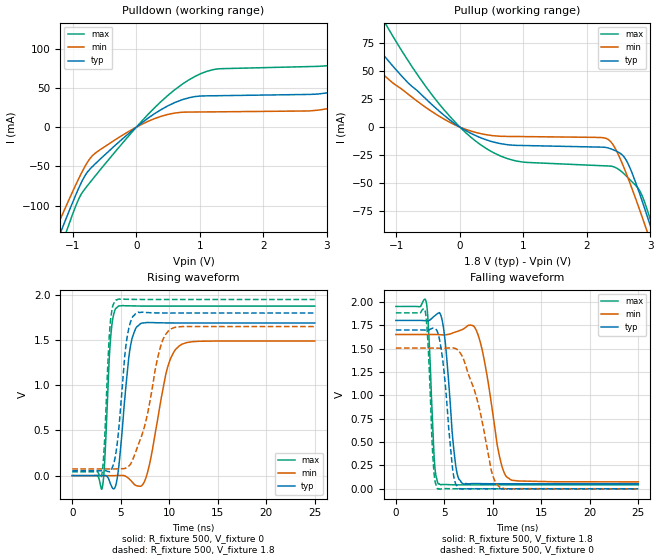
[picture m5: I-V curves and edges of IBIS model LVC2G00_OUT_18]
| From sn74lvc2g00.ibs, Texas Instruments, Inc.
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[Model]   LVC2G00_OUT_18
Model_type  Output
Vref =   0
Rref =   1000
Cref =   30p
Vmeas =   0.9
| variable   typ   min   max
C_comp   9.75pF   6.49pF   16.55pF
| C_pullup   8.84pF   6.49pF   9.71pF
| C_pulldown   10.67pF   6.61pF   16.55pF
[Temperature Range]   40   100   -40
| Ambient temperature   25   85   -40
[Voltage range]   1.8   1.65   1.95
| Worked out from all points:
|   slope of the pulldown table from 0 to 0.27 V, typ, clamps not added: 16.6 ohm
|   slope of the pullup table from 0 to 0.27 V, typ, clamps not added: 33.1 ohm
|   rising waveform, R_fixture 500, V_fixture 0: 20-80 % time 871ps typ, 1.53ns min, 493ps max; typ from 0 V to 1.69 V
|   falling waveform, R_fixture 500, V_fixture 1.8: 20-80 % time 794ps typ, 1.41ns min, 469ps max; typ from 1.8 V to 0.054 V
|   rising waveform, R_fixture 500, V_fixture 1.8: 20-80 % time 862ps typ, 1.9ns min, 483ps max; typ from 0.054 V to 1.8 V
|   falling waveform, R_fixture 500, V_fixture 0: 20-80 % time 877ps typ, 2.1ns min, 462ps max; typ from 1.7 V to 0 V
[Pulldown]
| LVC2G00_OUT_18
|   Voltage   I(typ)   I(min)   I(max)
-5.5V     -1.024A    -932.8mA   -1.143A
-1.25V    -145.7mA   -126.9mA   -167.2mA
-1.105V   -116mA     -100.2mA   -133.6mA
-650mV    -46.91mA   -33.3mA    -62.35mA
825mV     37.35mA    19.19mA    60.06mA
3.115V    45.51mA    25.21mA    79.67mA
3.75V     64.63mA    36.25mA    102.7mA
4.19V     79.74mA    21.53mA    128.8mA
4.47V     45.53mA    21.68mA    147.1mA
4.725V    44.49mA    21.83mA    132.4mA
5.015V    44.72mA    22mA       83.01mA
11V       50.72mA    25.33mA    92.94mA
[Pullup]
| LVC2G00_OUT_18
|   Voltage   I(typ)   I(min)   I(max)
-5.5V     463.8mA    356.2mA    652.9mA
-2.025V   127.2mA    95.17mA    184.5mA
-1.53V    88.09mA    64.89mA    129.3mA
-1.185V   63.28mA    45.93mA    93.85mA
-315mV    13.77mA    9.383mA    19.91mA
390mV     -10.87mA   -6.54mA    -18.23mA
990mV     -16.43mA   -8.453mA   -31.26mA
2.34V     -18.76mA   -11.2mA    -34.79mA
2.62V     -29.72mA   -41.58mA   -43.75mA
2.95V     -79.83mA   -93.7mA    -74.05mA
3.09V     -104.6mA   -117.3mA   -99.67mA
11V       -1.709A    -1.61A     -1.847A
[Ramp]
| LVC2G00_OUT_18
| variable   typ   min   max
dV/dt_r   1.10/9.55E-10   0.96/1.69E-09   1.22/5.50E-10
dV/dt_f   1.10/9.00E-10   1.00/1.57E-09   1.19/4.96E-10
R_load = 500
[Rising Waveform]
| LVC2G00_OUT_18
R_fixture =   500
C_fixture =   0
L_fixture =   0
V_fixture =   0
V_fixture_min = 0
V_fixture_max = 0
|   Time   V(typ)   V(min)   V(max)
0s        111.1pV    7.498nV    3.005nV
3.08ns    890.2uV    -71.22uV   -139.2mV
3.975ns   -99.86mV   -93.88uV   1.554V
4.73ns    43.52mV    1.986mV    1.874V
5.905ns   1.37V      -40.82mV   1.88V
6.985ns   1.678V     -117.8mV   1.877V
7.935ns   1.694V     113.8mV    1.877V
9.805ns   1.691V     1.191V     1.877V
11.02ns   1.69V      1.436V     1.877V
24.99ns   1.69V      1.49V      1.877V
[Falling Waveform]
| LVC2G00_OUT_18
R_fixture =   500
C_fixture =   0
L_fixture =   0
V_fixture =   1.8
V_fixture_min = 1.65
V_fixture_max = 1.95
|   Time   V(typ)   V(min)   V(max)
0s        1.8V       1.65V      1.95V
3.135ns   1.796V     1.65V      1.997V
3.955ns   1.845V     1.65V      326.6mV
4.395ns   1.879V     1.649V     51.32mV
5.045ns   1.613V     1.647V     45.43mV
6.195ns   232.7mV    1.678V     42.03mV
6.855ns   56.72mV    1.702V     41.68mV
8.595ns   55.18mV    1.609V     41.85mV
11.47ns   53.66mV    122.3mV    41.88mV
24.99ns   53.6mV     73.95mV    41.88mV
[Rising Waveform]
| LVC2G00_OUT_18
R_fixture =   500
C_fixture =   0
L_fixture =   0
V_fixture =   1.8
V_fixture_min = 1.65
V_fixture_max = 1.95
|   Time   V(typ)   V(min)   V(max)
0s        53.59mV    73.89mV    41.88mV
3.015ns   54.08mV    73.84mV    -5.701mV
3.29ns    56.58mV    73.8mV     309.5mV
3.875ns   43.25mV    73.86mV    1.637V
4.47ns    232.3mV    74.32mV    1.943V
5.615ns   1.507V     89.69mV    1.952V
6.61ns    1.801V     283.3mV    1.951V
9.095ns   1.801V     1.427V     1.95V
10.1ns    1.8V       1.619V     1.95V
24.99ns   1.8V       1.65V      1.95V
[Falling Waveform]
| LVC2G00_OUT_18
R_fixture =   500
C_fixture =   0
L_fixture =   0
V_fixture =   0
V_fixture_min = 0
V_fixture_max = 0
|   Time   V(typ)   V(min)   V(max)
0s        1.699V     1.505V     1.882V
3.015ns   1.697V     1.505V     1.906V
3.325ns   1.696V     1.505V     1.534V
3.89ns    1.718V     1.505V     233mV
4.32ns    1.67V      1.504V     -1.828mV
4.93ns    1.29V      1.503V     333.5uV
5.865ns   198.4mV    1.508V     259.6uV
6.495ns   2.21mV     1.472V     -200.6uV
10.7ns    29.26uV    16.62mV    2.635uV
24.99ns   8.489uV    22.77uV    3.874uV
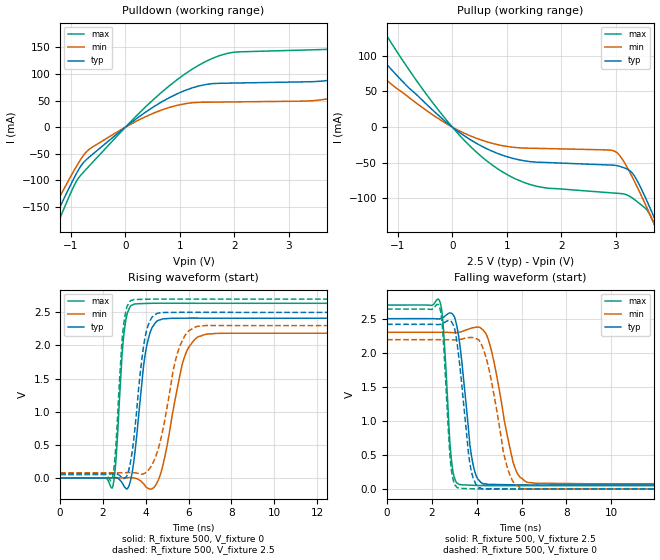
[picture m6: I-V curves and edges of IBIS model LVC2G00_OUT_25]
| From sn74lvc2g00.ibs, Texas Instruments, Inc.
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[Model]   LVC2G00_OUT_25
Model_type  Output
Vref =   0
Rref =   500
Cref =   30p
Vmeas =   1.25
| variable   typ   min   max
C_comp   9.50pF   6.28pF   13.67pF
| C_pullup   9.22pF   6.28pF   10.84pF
| C_pulldown   9.79pF   6.28pF   13.67pF
[Temperature Range]   40   100   -40
| Ambient temperature   25   85   -40
[Voltage range]   2.5   2.3   2.7
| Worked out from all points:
|   slope of the pulldown table from 0 to 0.375 V, typ, clamps not added: 13.1 ohm
|   slope of the pullup table from 0 to 0.375 V, typ, clamps not added: 19 ohm
|   rising waveform, R_fixture 500, V_fixture 0: 20-80 % time 479ps typ, 770ps min, 299ps max; typ from 0 V to 2.41 V
|   falling waveform, R_fixture 500, V_fixture 2.5: 20-80 % time 451ps typ, 760ps min, 277ps max; typ from 2.5 V to 0.06 V
|   rising waveform, R_fixture 500, V_fixture 2.5: 20-80 % time 483ps typ, 803ps min, 297ps max; typ from 0.06 V to 2.5 V
|   falling waveform, R_fixture 500, V_fixture 0: 20-80 % time 445ps typ, 715ps min, 275ps max; typ from 2.42 V to 0 V
[Pulldown]
| LVC2G00_OUT_25
|   Voltage   I(typ)   I(min)   I(max)
-5.5V     -1.065A    -962.2mA   -1.199A
-1.53V    -221.1mA   -193.8mA   -251.2mA
-1.17V    -142.7mA   -123.7mA   -162.8mA
-670mV    -56.67mA   -41.91mA   -73.36mA
520mV     38.43mA    26.46mA    52.49mA
1.485V    80.34mA    46.87mA    124mA
3.845V    90.19mA    55.77mA    148mA
5.34V     158.2mA    106.6mA    232.1mA
5.845V    188.2mA    52.6mA     277.9mA
6.525V    93.64mA    53.14mA    300.5mA
7.565V    94.13mA    54.13mA    160.8mA
11V       99.66mA    57.57mA    168.9mA
[Pullup]
| LVC2G00_OUT_25
|   Voltage   I(typ)   I(min)   I(max)
-5.5V     540.5mA    425.9mA    755.1mA
-2.25V    184.3mA    140.8mA    263.9mA
-1.8V     141.1mA    106.9mA    203.3mA
-1.375V   102.6mA    76.95mA    148.9mA
-70mV     4.265mA    3.049mA    6.405mA
730mV     -33.72mA   -22.66mA   -53.01mA
1.56V     -49.18mA   -29.79mA   -83.17mA
2.995V    -53.63mA   -34.3mA    -92.61mA
3.315V    -65.3mA    -71.46mA   -99.87mA
3.565V    -101.9mA   -111.4mA   -115.4mA
3.75V     -134.3mA   -142.6mA   -143.5mA
11V       -1.614A    -1.516A    -1.761A
[Ramp]
| LVC2G00_OUT_25
| variable   typ   min   max
dV/dt_r   1.55/5.35E-10   1.41/8.47E-10   1.68/3.29E-10
dV/dt_f   1.51/4.93E-10   1.38/8.23E-10   1.64/2.96E-10
R_load = 500
[Rising Waveform]
| LVC2G00_OUT_25
R_fixture =   500
C_fixture =   0
L_fixture =   0
V_fixture =   0
V_fixture_min = 0
V_fixture_max = 0
|   Time   V(typ)   V(min)   V(max)
0s        123.6pV    5.747nV    2.756nV
2.44ns    1.412mV    -38.45uV   -147.8mV
2.605ns   3.732mV    -160.8uV   268.9mV
2.99ns    -128.3mV   630.5uV    2.207V
3.465ns   308.9mV    -1.698mV   2.626V
4.01ns    1.936V     -137.1mV   2.635V
4.6ns     2.383V     -21.45mV   2.638V
5.765ns   2.413V     1.783V     2.638V
6.715ns   2.413V     2.162V     2.637V
24.99ns   2.412V     2.184V     2.637V
[Falling Waveform]
| LVC2G00_OUT_25
R_fixture =   500
C_fixture =   0
L_fixture =   0
V_fixture =   2.5
V_fixture_min = 2.3
V_fixture_max = 2.7
|   Time   V(typ)   V(min)   V(max)
0s        2.5V       2.3V       2.7V
2.35ns    2.498V     2.3V       2.756V
2.505ns   2.518V     2.3V       2.393V
2.87ns    2.581V     2.296V     427.8mV
3.23ns    2.155V     2.302V     66.3mV
3.77ns    477.1mV    2.362V     55.47mV
4.28ns    77.28mV    2.333V     50.42mV
5.625ns   61.73mV    387.1mV    48.89mV
6.26ns    60.08mV    97.17mV    49.17mV
24.99ns   60.1mV     77.09mV    49.34mV
[Rising Waveform]
| LVC2G00_OUT_25
R_fixture =   500
C_fixture =   0
L_fixture =   0
V_fixture =   2.5
V_fixture_min = 2.3
V_fixture_max = 2.7
|   Time   V(typ)   V(min)   V(max)
0s        60.06mV    77.04mV    49.31mV
2.425ns   61.28mV    77.01mV    -20.94mV
2.585ns   64.25mV    76.9mV     407mV
2.945ns   -3.35mV    77.42mV    2.256V
3.32ns    303.2mV    81.63mV    2.682V
3.95ns    2.092V     71.01mV    2.698V
4.56ns    2.488V     416.3mV    2.701V
5.5ns     2.5V       1.905V     2.701V
6.375ns   2.501V     2.286V     2.7V
24.99ns   2.5V       2.3V       2.7V
[Falling Waveform]
| LVC2G00_OUT_25
R_fixture =   500
C_fixture =   0
L_fixture =   0
V_fixture =   0
V_fixture_min = 0
V_fixture_max = 0
|   Time   V(typ)   V(min)   V(max)
0s        2.416V     2.191V     2.64V
2.33ns    2.414V     2.192V     2.679V
2.48ns    2.428V     2.192V     2.323V
2.84ns    2.463V     2.188V     367.4mV
3.155ns   2.057V     2.19V      16.47mV
3.71ns    345.3mV    2.224V     4.819mV
4.255ns   2.025mV    2.085V     898.4uV
5.33ns    2.084mV    353.4mV    -431.4uV
6.025ns   40.29uV    6.866mV    -164.5uV
24.99ns   29.16uV    44.31uV    23.85uV
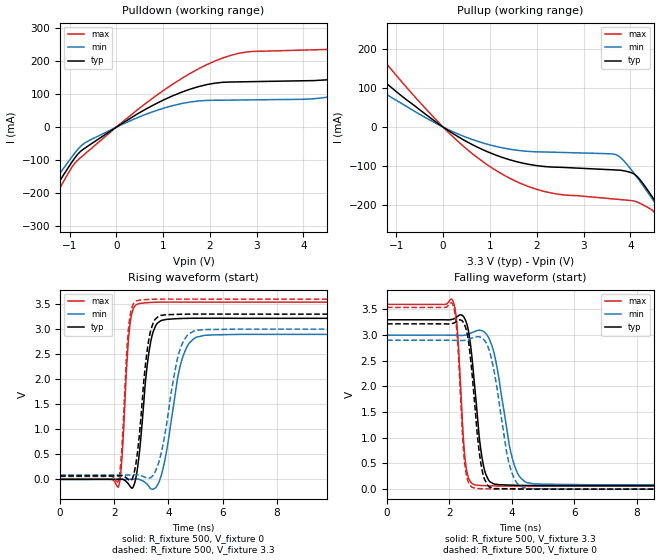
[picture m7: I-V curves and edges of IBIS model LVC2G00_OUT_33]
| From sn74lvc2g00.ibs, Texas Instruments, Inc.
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[Model]   LVC2G00_OUT_33
Model_type  Output
Vref =   0
Rref =   500
Cref =   50p
Vmeas =   1.5
| variable   typ   min   max
C_comp   9.16pF   6.01pF   12.68pF
| C_pullup   9.33pF   6.01pF   11.08pF
| C_pulldown   8.99pF   6.09pF   12.68pF
[Temperature Range]   40   100   -40
| Ambient temperature   25   85   -40
[Voltage range]   3.3   3   3.6
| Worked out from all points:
|   slope of the pulldown table from 0 to 0.495 V, typ, clamps not added: 11.3 ohm
|   slope of the pullup table from 0 to 0.495 V, typ, clamps not added: 13.5 ohm
|   rising waveform, R_fixture 500, V_fixture 0: 20-80 % time 342ps typ, 523ps min, 214ps max; typ from 0 V to 3.22 V
|   falling waveform, R_fixture 500, V_fixture 3.3: 20-80 % time 312ps typ, 476ps min, 195ps max; typ from 3.3 V to 0.069 V
|   rising waveform, R_fixture 500, V_fixture 3.3: 20-80 % time 341ps typ, 546ps min, 211ps max; typ from 0.069 V to 3.3 V
|   falling waveform, R_fixture 500, V_fixture 0: 20-80 % time 303ps typ, 456ps min, 192ps max; typ from 3.22 V to 0 V
[Pulldown]
| LVC2G00_OUT_33
|   Voltage   I(typ)   I(min)   I(max)
-5.5V     -1.112A    -993.8mA   -1.259A
-2.645V   -490.3mA   -433.2mA   -553.8mA
-1.49V    -226.9mA   -197.7mA   -257.3mA
-660mV    -62.56mA   -46.68mA   -79.82mA
1.935V    128.9mA    81.03mA    189.3mA
4.97V     155.6mA    103.9mA    243.7mA
6.025V    209.8mA    152.2mA    306.6mA
6.98V     279.9mA    202.8mA    397.5mA
7.255V    302.2mA    148.3mA    427.8mA
7.84V     331.9mA    92.56mA    496.3mA
8.75V     171.1mA    93.27mA    503mA
11V       160mA      96.49mA    277.2mA
[Pullup]
| LVC2G00_OUT_33
|   Voltage   I(typ)   I(min)   I(max)
-5.5V     614.6mA    484.1mA    860.6mA
-3.195V   331.2mA    256.4mA    470.1mA
-2.445V   244.5mA    187.5mA    349.2mA
-1.9V     184mA      140mA      264.4mA
-25mV     2.068mA    1.503mA    3.07mA
1.03V     -66.98mA   -46.4mA    -103.2mA
2.145V    -100.4mA   -63.42mA   -163.8mA
3.715V    -109.6mA   -71.54mA   -184.3mA
4.15V     -126.7mA   -129.5mA   -191.6mA
4.77V     -234mA     -236.5mA   -264.4mA
4.955V    -269.4mA   -269.8mA   -302.3mA
11V       -1.523A    -1.428A    -1.684A
[Ramp]
| LVC2G00_OUT_33
| variable   typ   min   max
dV/dt_r   2.04/3.68E-10   1.85/5.83E-10   2.22/2.28E-10
dV/dt_f   1.99/3.33E-10   1.81/5.23E-10   2.19/2.09E-10
R_load = 500
[Rising Waveform]
| LVC2G00_OUT_33
R_fixture =   500
C_fixture =   0
L_fixture =   0
V_fixture =   0
V_fixture_min = 0
V_fixture_max = 0
|   Time   V(typ)   V(min)   V(max)
0s        141.8pV    4.978nV    2.659nV
2.155ns   1.621mV    -55.46uV   -146.4mV
2.285ns   4.333mV    -124.6uV   452mV
2.565ns   -124.8mV   775uV      3.033V
2.925ns   527.8mV    -1.579mV   3.512V
3.23ns    2.345V     -107.9mV   3.53V
3.505ns   3.041V     -177mV     3.537V
4.475ns   3.213V     2.351V     3.54V
5.075ns   3.219V     2.848V     3.54V
24.99ns   3.217V     2.895V     3.539V
[Falling Waveform]
| LVC2G00_OUT_33
R_fixture =   500
C_fixture =   0
L_fixture =   0
V_fixture =   3.3
V_fixture_min = 3
V_fixture_max = 3.6
|   Time   V(typ)   V(min)   V(max)
0s        3.3V       3V         3.6V
2.11ns    3.311V     2.999V     3.67V
2.25ns    3.362V     2.997V     3.127V
2.51ns    3.294V     3V         530mV
2.825ns   1.886V     3.076V     81.85mV
3.02ns    697mV      3.09V      70.75mV
3.24ns    188.8mV    2.967V     65.91mV
4.015ns   77.82mV    592.3mV    59.06mV
4.5ns     71.57mV    124.5mV    58.53mV
24.99ns   69.38mV    85.92mV    58.95mV
[Rising Waveform]
| LVC2G00_OUT_33
R_fixture =   500
C_fixture =   0
L_fixture =   0
V_fixture =   3.3
V_fixture_min = 3
V_fixture_max = 3.6
|   Time   V(typ)   V(min)   V(max)
0s        69.35mV    85.87mV    58.92mV
2.145ns   70.73mV    85.82mV    -41.01mV
2.27ns    73.55mV    85.75mV    559mV
2.535ns   -9.88mV    86.3mV     3.07V
2.835ns   451.1mV    92.64mV    3.569V
3.265ns   2.762V     26.78mV    3.594V
3.705ns   3.274V     466.1mV    3.6V
4.38ns    3.296V     2.512V     3.601V
5.02ns    3.301V     2.976V     3.6V
24.99ns   3.3V       3V         3.6V
[Falling Waveform]
| LVC2G00_OUT_33
R_fixture =   500
C_fixture =   0
L_fixture =   0
V_fixture =   0
V_fixture_min = 0
V_fixture_max = 0
|   Time   V(typ)   V(min)   V(max)
0s        3.22V      2.9V       3.542V
2.1ns     3.229V     2.9V       3.603V
2.24ns    3.271V     2.898V     3.042V
2.495ns   3.182V     2.9V       460.6mV
2.82ns    1.573V     2.963V     16.96mV
3.005ns   502.1mV    2.956V     8.313mV
3.21ns    87.2mV     2.812V     5.597mV
3.915ns   7.203mV    482.7mV    276.4uV
4.39ns    2.341mV    27.97mV    -370.7uV
24.99ns   29.19uV    38.75uV    24.67uV
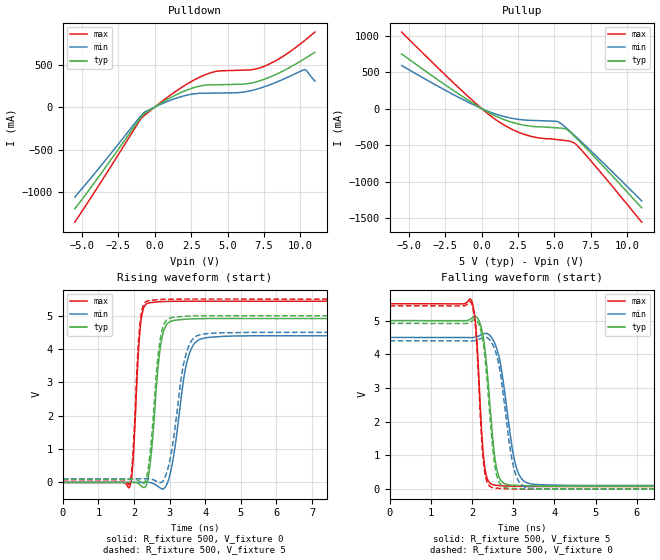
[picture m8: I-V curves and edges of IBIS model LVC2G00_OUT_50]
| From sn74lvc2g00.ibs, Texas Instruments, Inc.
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[Model]   LVC2G00_OUT_50
Model_type  Output
Vref =   0
Rref =   500
Cref =   50p
Vmeas =   2.5
| variable   typ   min   max
C_comp   8.59pF   5.65pF   11.12pF
| C_pullup   9.16pF   5.65pF   11.09pF
| C_pulldown   8.02pF   5.91pF   11.12pF
[Temperature Range]   40   100   -40
| Ambient temperature   25   85   -40
[Voltage range]   5   4.5   5.5
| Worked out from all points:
|   slope of the pulldown table from 0 to 0.75 V, typ, clamps not added: 9.58 ohm
|   slope of the pullup table from 0 to 0.75 V, typ, clamps not added: 9.16 ohm
|   rising waveform, R_fixture 500, V_fixture 0: 20-80 % time 231ps typ, 343ps min, 154ps max; typ from 0 V to 4.92 V
|   falling waveform, R_fixture 500, V_fixture 5: 20-80 % time 214ps typ, 304ps min, 148ps max; typ from 5 V to 0.09 V
|   rising waveform, R_fixture 500, V_fixture 5: 20-80 % time 229ps typ, 347ps min, 153ps max; typ from 0.09 V to 5 V
|   falling waveform, R_fixture 500, V_fixture 0: 20-80 % time 211ps typ, 293ps min, 145ps max; typ from 4.92 V to 0 V
[Pulldown]
| LVC2G00_OUT_50
|   Voltage   I(typ)   I(min)   I(max)
-5.5V     -1.198A    -1.059A    -1.354A
-970mV    -125.1mA   -106.1mA   -141.7mA
-680mV    -74.91mA   -57.01mA   -93.43mA
195mV     21.21mA    15.8mA     26.64mA
1.895V    178.4mA    126.5mA    236.9mA
3.275V    252.9mA    162.3mA    366.5mA
4.325V    262.7mA    164.8mA    422.2mA
5.82V     267.9mA    170.8mA    433mA
7.315V    314.3mA    227mA      466.3mA
8.65V     410.9mA    313.7mA    579.5mA
10.28V    567mA      439.5mA    779.7mA
11V       643.8mA    306.6mA    881.7mA
[Pullup]
| LVC2G00_OUT_50
|   Voltage   I(typ)   I(min)   I(max)
-5.5V     748.7mA    590.8mA    1.049A
-1.265V   158.7mA    121.2mA    227.5mA
150mV     -17.67mA   -13.2mA    -25.77mA
1.03V     -108.3mA   -79.33mA   -160.2mA
2.04V     -185.1mA   -131.6mA   -279.5mA
3.045V    -232.5mA   -158.6mA   -361mA
3.945V    -250.5mA   -165.3mA   -402.5mA
5.3V      -265.9mA   -185.4mA   -427.7mA
5.83V     -285.1mA   -268.2mA   -440mA
6.525V    -410.2mA   -394.3mA   -498.1mA
8.085V    -732.8mA   -692.6mA   -852.4mA
11V       -1.361A    -1.267A    -1.557A
[Ramp]
| LVC2G00_OUT_50
| variable   typ   min   max
dV/dt_r   3.05/2.44E-10   2.76/3.71E-10   3.36/1.64E-10
dV/dt_f   3.02/2.26E-10   2.71/3.27E-10   3.33/1.58E-10
R_load = 500
[Rising Waveform]
| LVC2G00_OUT_50
R_fixture =   500
C_fixture =   0
L_fixture =   0
V_fixture =   0
V_fixture_min = 0
V_fixture_max = 0
|   Time   V(typ)   V(min)   V(max)
0s        181.8pV    4.248nV    2.638nV
1.885ns   1.062mV    -39.71uV   -123mV
1.975ns   3.885mV    -71.6uV    682.3mV
2.18ns    -80.86mV   731.6uV    4.677V
2.41ns    210.2mV    3.09mV     5.381V
2.76ns    4.178V     -179.3mV   5.423V
3.135ns   4.862V     936.5mV    5.434V
3.525ns   4.901V     3.754V     5.436V
4.025ns   4.915V     4.341V     5.436V
24.99ns   4.915V     4.397V     5.436V
[Falling Waveform]
| LVC2G00_OUT_50
R_fixture =   500
C_fixture =   0
L_fixture =   0
V_fixture =   5
V_fixture_min = 4.5
V_fixture_max = 5.5
|   Time   V(typ)   V(min)   V(max)
0s        5V         4.5V       5.5V
1.98ns    5.059V     4.495V     5.609V
2.095ns   5.125V     4.513V     4.785V
2.24ns    4.712V     4.59V      1.566V
2.3ns     4.277V     4.618V     726.2mV
2.545ns   1.012V     4.34V      122mV
2.685ns   284.3mV    3.752V     102.7mV
3.045ns   114.2mV    782.2mV    84.73mV
3.405ns   98.54mV    160mV      80.32mV
24.99ns   89.63mV    107.6mV    78.97mV
[Rising Waveform]
| LVC2G00_OUT_50
R_fixture =   500
C_fixture =   0
L_fixture =   0
V_fixture =   5
V_fixture_min = 4.5
V_fixture_max = 5.5
|   Time   V(typ)   V(min)   V(max)
0s        89.62mV    107.6mV    78.96mV
1.875ns   90.5mV     107.6mV    -34.59mV
1.97ns    93.26mV    107.5mV    837.4mV
2.17ns    25.91mV    108.2mV    4.764V
2.405ns   458.3mV    111.6mV    5.45V
2.74ns    4.309V     -1.869mV   5.487V
3.105ns   4.952V     1.264V     5.498V
3.47ns    4.987V     3.874V     5.5V
3.94ns    5V         4.452V     5.5V
24.99ns   5V         4.5V       5.5V
[Falling Waveform]
| LVC2G00_OUT_50
R_fixture =   500
C_fixture =   0
L_fixture =   0
V_fixture =   0
V_fixture_min = 0
V_fixture_max = 0
|   Time   V(typ)   V(min)   V(max)
0s        4.917V     4.401V     5.437V
1.975ns   4.97V      4.396V     5.542V
2.09ns    5.029V     4.412V     4.716V
2.23ns    4.616V     4.478V     1.543V
2.285ns   4.215V     4.503V     709mV
2.52ns    1.005V     4.239V     40.2mV
2.675ns   167.1mV    3.533V     20.84mV
3.02ns    20mV       594.2mV    5.58mV
3.405ns   6.897mV    27.56mV    1.288mV
24.99ns   8.131uV    12uV       8.732uV
